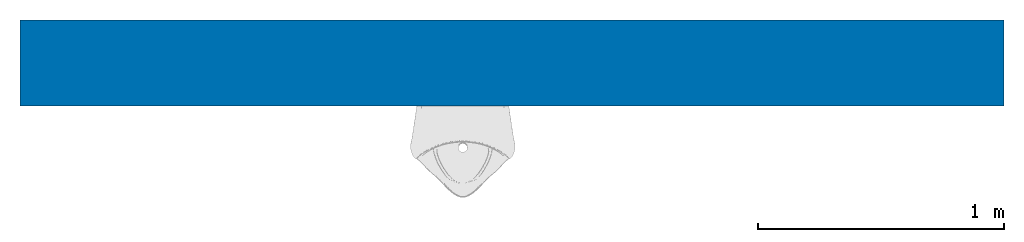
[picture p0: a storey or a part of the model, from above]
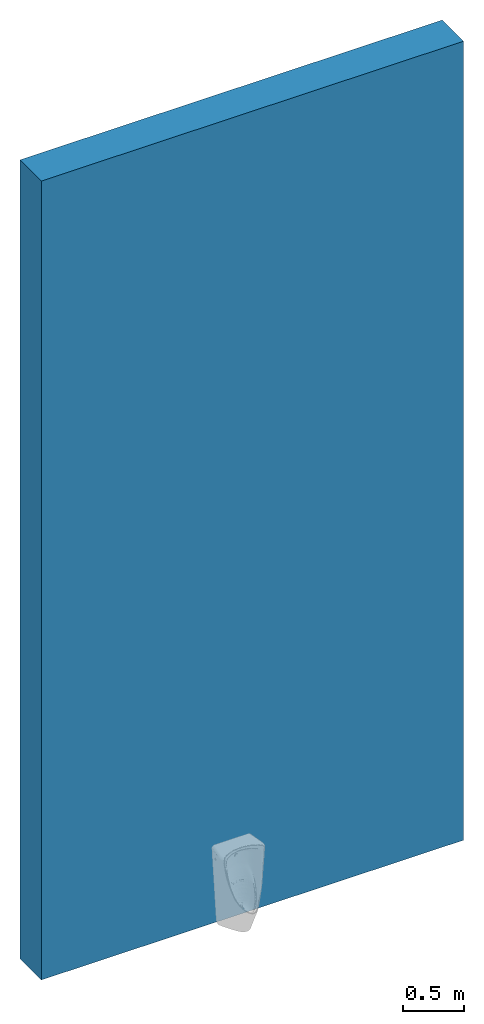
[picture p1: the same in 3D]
Properties of the parts of a building model (IFC2X3)

# File
Description: ViewDefinition [CoordinationView_V2.0]
File name: 0001
Time: 2024-08-25T14:03:10
Written by: The EXPRESS Data Manager Version 5.02.0100.07 : 28 Aug 2013
Made in: 21.1.90.15 - Exporter 21.1.90.15 - Alternate UI 21.1.90.15
Comment: STEP Physical File produced by: The EXPRESS Data Manager Version 5.02.0100.07 : 28 Aug 2013 * Module: EDMstepFileFactory/EDMstandAlone * Creation date: Sun Aug 25 14:03:10 2024 * Host: DCreative * Database: C:\Users\chatp\AppData\Local\Temp\3211e499-1c11-4351-9318-3c50579a1372\1f5db18a-d617-484c-a7ff-3e975091a6a2\ifc * Database version: 5507 * Database creation date: Sun Aug 25 14:03:03 2024 * Schema: IFC2X3 * Model: DataRepository.ifc * Model creation date: Sun Aug 25 14:03:03 2024 * Header model: DataRepository.ifc_HeaderModel * Header model creation date: Sun Aug 25 14:03:03 2024 * EDMuser: sdai-user * EDMgroup: sdai-group * License ID and type: 5605 : Permanent license. Expiry date: * EDMstepFileFactory options: 020000

# IfcProject, 0001
LongName: Project Name; Phase: Project Status

# IfcSite, Default
RefLatitude: 42, 21, 31, 181945; RefLongitude: -71, -3, -24, -263305; RefElevation: 0 mm
Pset_ProductRequirements - Category: Project Information

# IfcBuilding
Pset_BuildingCommon - NumberOfStoreys: 1
Pset_ProductRequirements - Category: Project Information

# IfcBuildingStorey: Level:8mm Head, Level 1
LongName: Level 1; Elevation: 0 mm
Pset_AirSideSystemInformation - Name: Level 1
Pset_ProductRequirements - Name: Level 1; Category: Levels

# IfcBuildingElementProxy: CCAS6519-3130410F0_REVIT:Lynbrook Int. Sensor WH Urinal w ManualOverride, CCAS6519-3130410F0_REVIT:Lynbrook Int. Sensor WH Urinal w ManualOverride:348891
In: Level 1
Type - Material: American Standard - Chrome, American Standard - Zinc Die Cast-Plastic
Type - Pset_BuildingElementProxyCommon - Reference: Lynbrook Int. Sensor WH Urinal w ManualOverride
Type - Pset_ManufacturerTypeInformation - Manufacturer: American Standard
Type - Pset_ProductRequirements - Category: Specialty Equipment
Type - Pset_QuantityTakeOff - Reference: Lynbrook Int. Sensor WH Urinal w ManualOverride
Type - Pset_ProvisionForVoid - Width: 372 mm; Height: 780 mm
Material: American Standard - Chrome
Pset_BuildingElementProxyCommon - sets with these values: 2

# IfcDistributionPort, Port_348891
Description: Flow; FlowDirection: SINK

# IfcWallStandardCase: Basic Wall:Exterior - Brick on Mtl. Stud, Basic Wall:Exterior - Brick on Mtl. Stud:348881
In: Level 1
Type - PredefinedType: STANDARD
Type - Pset_ElementShading - Roughness: 914.4 mm
Type - Pset_ProductRequirements - Category: Walls
Type - Pset_QuantityTakeOff - Reference: Exterior - Brick on Mtl. Stud
Type - Pset_ReinforcementBarPitchOfWall - Reference: Exterior - Brick on Mtl. Stud
Type - Pset_WallCommon - Reference: Exterior - Brick on Mtl. Stud; IsExternal: no
Pset_QuantityTakeOff - sets with these values: 2
Pset_WallCommon - IsExternal: yes; ExtendToStructure: no; LoadBearing: no
